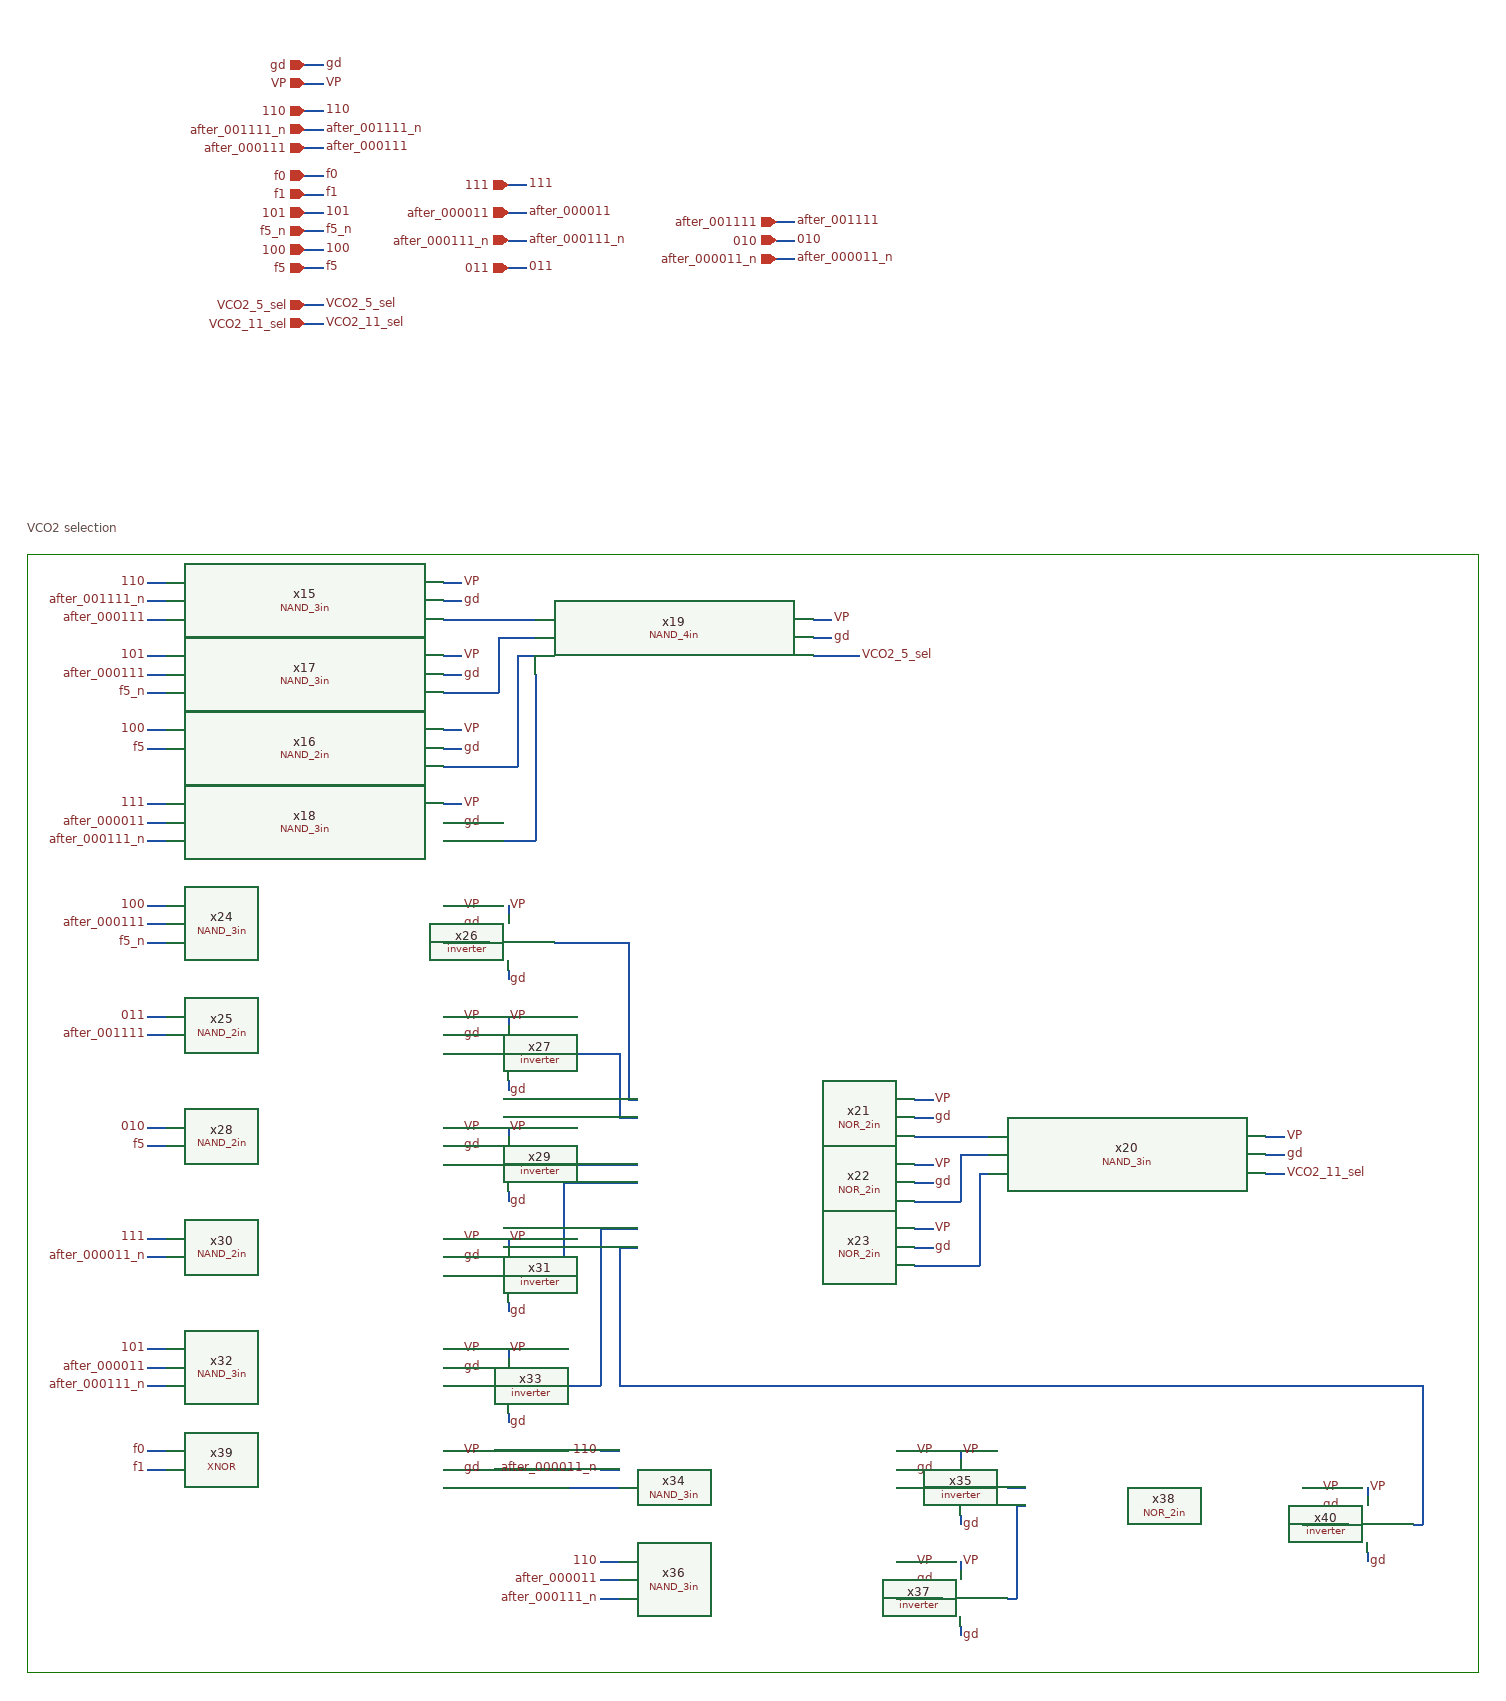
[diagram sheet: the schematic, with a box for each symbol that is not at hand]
v {xschem version=3.4.8RC file_version=1.3}
G {}
K {}
V {}
S {}
F {}
E {}
L 4 1700 -2770 1700 -2430 {}
L 4 1700 -2770 2040 -2770 {}
L 4 2040 -2770 2380 -2770 {}
L 4 2380 -2770 2720 -2770 {}
L 4 1700 -2440 1700 -2100 {}
L 4 1700 -2280 1700 -1940 {}
L 4 1700 -1950 1700 -1610 {}
L 4 1700 -1560 2040 -1560 {}
L 4 2040 -1560 2380 -1560 {}
L 4 2380 -1560 2720 -1560 {}
L 4 1700 -1900 1700 -1560 {}
L 4 2710 -2770 3050 -2770 {}
L 4 3270 -1900 3270 -1560 {}
L 4 2700 -1560 3040 -1560 {}
L 4 2930 -1560 3270 -1560 {}
L 4 3270 -2230 3270 -1890 {}
L 4 3270 -2570 3270 -2230 {}
L 4 3270 -2770 3270 -2430 {}
L 4 2930 -2770 3270 -2770 {}
T {VCO2 selection} 1700 -2810 0 0 0.4 0.4 {}
N 2150 -2720 2170 -2720 {lab=gd}
N 2150 -2740 2170 -2740 {lab=VP}
N 2150 -2560 2170 -2560 {lab=gd}
N 2150 -2580 2170 -2580 {lab=VP}
N 2150 -2640 2170 -2640 {lab=gd}
N 2150 -2660 2170 -2660 {lab=VP}
N 2150 -2480 2170 -2480 {lab=gd}
N 2150 -2500 2170 -2500 {lab=VP}
N 1830 -2740 1850 -2740 {lab=110}
N 1830 -2720 1850 -2720 {lab=after_001111_n}
N 1830 -2700 1850 -2700 {lab=after_000111}
N 1830 -2660 1850 -2660 {lab=101}
N 1830 -2640 1850 -2640 {lab=after_000111}
N 1830 -2620 1850 -2620 {lab=f5_n}
N 1830 -2500 1850 -2500 {lab=111}
N 1830 -2460 1850 -2460 {lab=after_000111_n}
N 1830 -2580 1850 -2580 {lab=100}
N 1830 -2560 1850 -2560 {lab=f5}
N 2150 -2700 2250 -2700 {lab=#net1}
N 2150 -2620 2210 -2620 {lab=#net2}
N 2210 -2680 2210 -2620 {lab=#net2}
N 2210 -2680 2250 -2680 {lab=#net2}
N 2230 -2660 2250 -2660 {lab=#net3}
N 2230 -2660 2230 -2540 {lab=#net3}
N 2150 -2540 2230 -2540 {lab=#net3}
N 2150 -2460 2250 -2460 {lab=#net4}
N 2250 -2640 2250 -2460 {lab=#net4}
N 2550 -2680 2570 -2680 {lab=gd}
N 2550 -2700 2570 -2700 {lab=VP}
N 2550 -2660 2600 -2660 {lab=VCO2_5_sel}
N 2660 -2160 2680 -2160 {lab=gd}
N 2660 -2180 2680 -2180 {lab=VP}
N 2660 -2090 2680 -2090 {lab=gd}
N 2660 -2110 2680 -2110 {lab=VP}
N 2660 -2020 2680 -2020 {lab=gd}
N 2660 -2040 2680 -2040 {lab=VP}
N 3040 -2120 3060 -2120 {lab=gd}
N 3040 -2140 3060 -2140 {lab=VP}
N 2660 -2140 2740 -2140 {lab=#net5}
N 2660 -2070 2710 -2070 {lab=#net6}
N 2710 -2120 2710 -2070 {lab=#net6}
N 2710 -2120 2740 -2120 {lab=#net6}
N 2730 -2100 2740 -2100 {lab=#net7}
N 2730 -2100 2730 -2000 {lab=#net7}
N 2660 -2000 2730 -2000 {lab=#net7}
N 2150 -2370 2170 -2370 {lab=gd}
N 2150 -2390 2170 -2390 {lab=VP}
N 2150 -2250 2170 -2250 {lab=gd}
N 2150 -2270 2170 -2270 {lab=VP}
N 2220 -2320 2220 -2310 {lab=gd}
N 2220 -2390 2220 -2380 {lab=VP}
N 2150 -2350 2200 -2350 {lab=#net8}
N 2270 -2350 2350 -2350 {lab=#net9}
N 2220 -2200 2220 -2190 {lab=gd}
N 2220 -2270 2220 -2260 {lab=VP}
N 2150 -2230 2200 -2230 {lab=#net10}
N 2270 -2230 2340 -2230 {lab=#net11}
N 2150 -2130 2170 -2130 {lab=gd}
N 2150 -2150 2170 -2150 {lab=VP}
N 2220 -2080 2220 -2070 {lab=gd}
N 2220 -2150 2220 -2140 {lab=VP}
N 2150 -2110 2200 -2110 {lab=#net12}
N 2270 -2110 2360 -2110 {lab=#net13}
N 2150 -2010 2170 -2010 {lab=gd}
N 2150 -2030 2170 -2030 {lab=VP}
N 2220 -1960 2220 -1950 {lab=gd}
N 2220 -2030 2220 -2020 {lab=VP}
N 2150 -1990 2200 -1990 {lab=#net14}
N 2270 -1990 2280 -1990 {lab=#net15}
N 2150 -1890 2170 -1890 {lab=gd}
N 2150 -1910 2170 -1910 {lab=VP}
N 2220 -1840 2220 -1830 {lab=gd}
N 2220 -1910 2220 -1900 {lab=VP}
N 2150 -1870 2200 -1870 {lab=#net16}
N 2270 -1870 2320 -1870 {lab=#net17}
N 2640 -1780 2660 -1780 {lab=gd}
N 2640 -1800 2660 -1800 {lab=VP}
N 2710 -1730 2710 -1720 {lab=gd}
N 2710 -1800 2710 -1790 {lab=VP}
N 2640 -1760 2690 -1760 {lab=#net18}
N 2760 -1760 2780 -1760 {lab=#net19}
N 2640 -1660 2660 -1660 {lab=gd}
N 2640 -1680 2660 -1680 {lab=VP}
N 2710 -1610 2710 -1600 {lab=gd}
N 2710 -1680 2710 -1670 {lab=VP}
N 2640 -1640 2690 -1640 {lab=#net20}
N 2760 -1640 2770 -1640 {lab=#net21}
N 2350 -2180 2360 -2180 {lab=#net9}
N 2350 -2350 2350 -2180 {lab=#net9}
N 2340 -2230 2340 -2160 {lab=#net11}
N 2340 -2160 2360 -2160 {lab=#net11}
N 2280 -2090 2280 -1990 {lab=#net15}
N 2280 -2090 2360 -2090 {lab=#net15}
N 2320 -2040 2320 -1870 {lab=#net17}
N 2320 -2040 2360 -2040 {lab=#net17}
N 3080 -1740 3100 -1740 {lab=gd}
N 3080 -1760 3100 -1760 {lab=VP}
N 3150 -1690 3150 -1680 {lab=gd}
N 3150 -1760 3150 -1750 {lab=VP}
N 3080 -1720 3130 -1720 {lab=#net22}
N 3200 -1720 3210 -1720 {lab=#net23}
N 2770 -1740 2780 -1740 {lab=#net21}
N 2770 -1740 2770 -1640 {lab=#net21}
N 2340 -2020 2340 -1870 {lab=#net23}
N 2340 -2020 2360 -2020 {lab=#net23}
N 2150 -1780 2170 -1780 {lab=gd}
N 2150 -1800 2170 -1800 {lab=VP}
N 3210 -1870 3210 -1720 {lab=#net23}
N 2340 -1870 3210 -1870 {lab=#net23}
N 1830 -2480 1850 -2480 {lab=after_000011}
N 1830 -2390 1850 -2390 {lab=100}
N 1830 -2350 1850 -2350 {lab=f5_n}
N 1830 -2370 1850 -2370 {lab=after_000111}
N 1830 -1910 1850 -1910 {lab=101}
N 1830 -1870 1850 -1870 {lab=after_000111_n}
N 1830 -1890 1850 -1890 {lab=after_000011}
N 2320 -1680 2340 -1680 {lab=110}
N 2320 -1640 2340 -1640 {lab=after_000111_n}
N 2320 -1660 2340 -1660 {lab=after_000011}
N 1830 -1800 1850 -1800 {lab=f0}
N 1830 -1780 1850 -1780 {lab=f1}
N 2320 -1800 2340 -1800 {lab=110}
N 2320 -1780 2340 -1780 {lab=after_000011_n}
N 1830 -2150 1850 -2150 {lab=010}
N 1830 -2130 1850 -2130 {lab=f5}
N 1830 -2270 1850 -2270 {lab=011}
N 1830 -2250 1850 -2250 {lab=after_001111}
N 1830 -2030 1850 -2030 {lab=111}
N 1830 -2010 1850 -2010 {lab=after_000011_n}
N 2150 -1760 2340 -1760 {lab=#net24}
N 3040 -2100 3060 -2100 {lab=VCO2_11_sel}
N 2000 -3300 2020 -3300 {lab=gd}
N 2000 -3280 2020 -3280 {lab=VP}
N 2000 -3230 2020 -3230 {lab=after_001111_n}
N 2000 -3210 2020 -3210 {lab=after_000111}
N 2000 -3180 2020 -3180 {lab=f0}
N 2000 -3160 2020 -3160 {lab=f1}
N 2000 -3250 2020 -3250 {lab=110}
N 2000 -3020 2020 -3020 {lab=VCO2_11_sel}
N 2000 -3040 2020 -3040 {lab=VCO2_5_sel}
N 2000 -3140 2020 -3140 {lab=101}
N 2000 -3120 2020 -3120 {lab=f5_n}
N 2000 -3100 2020 -3100 {lab=100}
N 2000 -3080 2020 -3080 {lab=f5}
N 2220 -3080 2240 -3080 {lab=011}
N 2220 -3110 2240 -3110 {lab=after_000111_n}
N 2220 -3140 2240 -3140 {lab=after_000011}
N 2220 -3170 2240 -3170 {lab=111}
N 2510 -3090 2530 -3090 {lab=after_000011_n}
N 2510 -3110 2530 -3110 {lab=010}
N 2510 -3130 2530 -3130 {lab=after_001111}
C {lab_wire.sym} 1830 -2660 0 0 {name=p124 sig_type=std_logic lab=101}
C {lab_wire.sym} 1830 -2740 0 0 {name=p125 sig_type=std_logic lab=110}
C {NAND_3in.sym} 2000 -2720 0 0 {name=x15}
C {NAND_2in.sym} 2000 -2560 0 0 {name=x16}
C {lab_wire.sym} 2170 -2740 2 0 {name=p130 sig_type=std_logic lab=VP}
C {lab_wire.sym} 2170 -2720 2 0 {name=p131 sig_type=std_logic lab=gd}
C {lab_wire.sym} 2170 -2580 2 0 {name=p132 sig_type=std_logic lab=VP}
C {lab_wire.sym} 2170 -2560 2 0 {name=p133 sig_type=std_logic lab=gd}
C {NAND_3in.sym} 2000 -2640 0 0 {name=x17}
C {lab_wire.sym} 2170 -2660 2 0 {name=p134 sig_type=std_logic lab=VP}
C {lab_wire.sym} 2170 -2640 2 0 {name=p135 sig_type=std_logic lab=gd}
C {NAND_3in.sym} 2000 -2480 0 0 {name=x18}
C {lab_wire.sym} 2170 -2500 2 0 {name=p136 sig_type=std_logic lab=VP}
C {lab_wire.sym} 2170 -2480 2 0 {name=p137 sig_type=std_logic lab=gd}
C {lab_wire.sym} 1830 -2580 0 0 {name=p140 sig_type=std_logic lab=100}
C {lab_wire.sym} 1830 -2500 0 0 {name=p141 sig_type=std_logic lab=111}
C {lab_wire.sym} 1830 -2720 0 0 {name=p142 sig_type=std_logic lab=after_001111_n}
C {lab_wire.sym} 1830 -2700 0 0 {name=p145 sig_type=std_logic lab=after_000111}
C {lab_wire.sym} 1830 -2640 0 0 {name=p146 sig_type=std_logic lab=after_000111}
C {lab_wire.sym} 1830 -2620 0 0 {name=p147 sig_type=std_logic lab=f5_n}
C {lab_wire.sym} 1830 -2560 0 0 {name=p90 sig_type=std_logic lab=f5}
C {lab_wire.sym} 1830 -2480 0 0 {name=p91 sig_type=std_logic lab=after_000011}
C {lab_wire.sym} 1830 -2460 0 0 {name=p94 sig_type=std_logic lab=after_000111_n}
C {NAND_4in.sym} 2400 -2670 0 0 {name=x19}
C {lab_wire.sym} 2570 -2700 2 0 {name=p148 sig_type=std_logic lab=VP}
C {lab_wire.sym} 2570 -2680 2 0 {name=p149 sig_type=std_logic lab=gd}
C {lab_wire.sym} 2600 -2660 2 0 {name=p150 sig_type=std_logic lab=VCO2_5_sel}
C {NAND_3in.sym} 2890 -2120 0 0 {name=x20}
C {NOR_2in.sym} 2510 -2160 0 0 {name=x21}
C {lab_wire.sym} 2680 -2180 2 0 {name=p151 sig_type=std_logic lab=VP}
C {lab_wire.sym} 2680 -2160 2 0 {name=p152 sig_type=std_logic lab=gd}
C {NOR_2in.sym} 2510 -2090 0 0 {name=x22}
C {lab_wire.sym} 2680 -2110 2 0 {name=p153 sig_type=std_logic lab=VP}
C {lab_wire.sym} 2680 -2090 2 0 {name=p154 sig_type=std_logic lab=gd}
C {NOR_2in.sym} 2510 -2020 0 0 {name=x23}
C {lab_wire.sym} 2680 -2040 2 0 {name=p155 sig_type=std_logic lab=VP}
C {lab_wire.sym} 2680 -2020 2 0 {name=p156 sig_type=std_logic lab=gd}
C {lab_wire.sym} 3060 -2140 2 0 {name=p157 sig_type=std_logic lab=VP}
C {lab_wire.sym} 3060 -2120 2 0 {name=p158 sig_type=std_logic lab=gd}
C {NAND_3in.sym} 2000 -2370 0 0 {name=x24}
C {lab_wire.sym} 2170 -2390 2 0 {name=p159 sig_type=std_logic lab=VP}
C {lab_wire.sym} 2170 -2370 2 0 {name=p160 sig_type=std_logic lab=gd}
C {NAND_2in.sym} 2000 -2250 0 0 {name=x25}
C {lab_wire.sym} 2170 -2270 2 0 {name=p161 sig_type=std_logic lab=VP}
C {lab_wire.sym} 2170 -2250 2 0 {name=p162 sig_type=std_logic lab=gd}
C {inverter.sym} 2220 -2350 0 0 {name=x26}
C {lab_wire.sym} 2220 -2390 0 1 {name=p163 sig_type=std_logic lab=VP}
C {lab_wire.sym} 2220 -2310 2 0 {name=p164 sig_type=std_logic lab=gd}
C {inverter.sym} 2220 -2230 0 0 {name=x27}
C {lab_wire.sym} 2220 -2270 0 1 {name=p165 sig_type=std_logic lab=VP}
C {lab_wire.sym} 2220 -2190 2 0 {name=p166 sig_type=std_logic lab=gd}
C {NAND_2in.sym} 2000 -2130 0 0 {name=x28}
C {lab_wire.sym} 2170 -2150 2 0 {name=p167 sig_type=std_logic lab=VP}
C {lab_wire.sym} 2170 -2130 2 0 {name=p168 sig_type=std_logic lab=gd}
C {inverter.sym} 2220 -2110 0 0 {name=x29}
C {lab_wire.sym} 2220 -2150 0 1 {name=p169 sig_type=std_logic lab=VP}
C {lab_wire.sym} 2220 -2070 2 0 {name=p170 sig_type=std_logic lab=gd}
C {NAND_2in.sym} 2000 -2010 0 0 {name=x30}
C {lab_wire.sym} 2170 -2030 2 0 {name=p171 sig_type=std_logic lab=VP}
C {lab_wire.sym} 2170 -2010 2 0 {name=p172 sig_type=std_logic lab=gd}
C {inverter.sym} 2220 -1990 0 0 {name=x31}
C {lab_wire.sym} 2220 -2030 0 1 {name=p173 sig_type=std_logic lab=VP}
C {lab_wire.sym} 2220 -1950 2 0 {name=p174 sig_type=std_logic lab=gd}
C {NAND_3in.sym} 2000 -1890 0 0 {name=x32}
C {lab_wire.sym} 2170 -1910 2 0 {name=p175 sig_type=std_logic lab=VP}
C {lab_wire.sym} 2170 -1890 2 0 {name=p176 sig_type=std_logic lab=gd}
C {inverter.sym} 2220 -1870 0 0 {name=x33}
C {lab_wire.sym} 2220 -1910 0 1 {name=p177 sig_type=std_logic lab=VP}
C {lab_wire.sym} 2220 -1830 2 0 {name=p178 sig_type=std_logic lab=gd}
C {NAND_3in.sym} 2490 -1780 0 0 {name=x34}
C {lab_wire.sym} 2660 -1800 2 0 {name=p179 sig_type=std_logic lab=VP}
C {lab_wire.sym} 2660 -1780 2 0 {name=p180 sig_type=std_logic lab=gd}
C {inverter.sym} 2710 -1760 0 0 {name=x35}
C {lab_wire.sym} 2710 -1800 0 1 {name=p181 sig_type=std_logic lab=VP}
C {lab_wire.sym} 2710 -1720 2 0 {name=p182 sig_type=std_logic lab=gd}
C {NAND_3in.sym} 2490 -1660 0 0 {name=x36}
C {lab_wire.sym} 2660 -1680 2 0 {name=p183 sig_type=std_logic lab=VP}
C {lab_wire.sym} 2660 -1660 2 0 {name=p184 sig_type=std_logic lab=gd}
C {inverter.sym} 2710 -1640 0 0 {name=x37}
C {lab_wire.sym} 2710 -1680 0 1 {name=p185 sig_type=std_logic lab=VP}
C {lab_wire.sym} 2710 -1600 2 0 {name=p186 sig_type=std_logic lab=gd}
C {NOR_2in.sym} 2930 -1740 0 0 {name=x38}
C {lab_wire.sym} 3100 -1760 2 0 {name=p189 sig_type=std_logic lab=VP}
C {lab_wire.sym} 3100 -1740 2 0 {name=p190 sig_type=std_logic lab=gd}
C {inverter.sym} 3150 -1720 0 0 {name=x40}
C {lab_wire.sym} 3150 -1760 0 1 {name=p191 sig_type=std_logic lab=VP}
C {lab_wire.sym} 3150 -1680 2 0 {name=p192 sig_type=std_logic lab=gd}
C {XNOR.sym} 2000 -1780 0 0 {name=x39}
C {lab_wire.sym} 2170 -1800 2 0 {name=p187 sig_type=std_logic lab=VP}
C {lab_wire.sym} 2170 -1780 2 0 {name=p188 sig_type=std_logic lab=gd}
C {lab_wire.sym} 1830 -2390 0 0 {name=p193 sig_type=std_logic lab=100}
C {lab_wire.sym} 1830 -2270 0 0 {name=p194 sig_type=std_logic lab=011}
C {lab_wire.sym} 1830 -2150 0 0 {name=p195 sig_type=std_logic lab=010}
C {lab_wire.sym} 1830 -2030 0 0 {name=p196 sig_type=std_logic lab=111}
C {lab_wire.sym} 1830 -1910 0 0 {name=p197 sig_type=std_logic lab=101}
C {lab_wire.sym} 2320 -1800 0 0 {name=p199 sig_type=std_logic lab=110}
C {lab_wire.sym} 2320 -1680 0 0 {name=p200 sig_type=std_logic lab=110}
C {lab_wire.sym} 1830 -2370 0 0 {name=p198 sig_type=std_logic lab=after_000111}
C {lab_wire.sym} 1830 -2350 0 0 {name=p201 sig_type=std_logic lab=f5_n}
C {lab_wire.sym} 1830 -2250 0 0 {name=p202 sig_type=std_logic lab=after_001111}
C {lab_wire.sym} 1830 -2130 0 0 {name=p203 sig_type=std_logic lab=f5}
C {lab_wire.sym} 1830 -2010 0 0 {name=p204 sig_type=std_logic lab=after_000011_n}
C {lab_wire.sym} 1830 -1890 0 0 {name=p205 sig_type=std_logic lab=after_000011}
C {lab_wire.sym} 1830 -1870 0 0 {name=p206 sig_type=std_logic lab=after_000111_n}
C {lab_wire.sym} 2320 -1780 0 0 {name=p207 sig_type=std_logic lab=after_000011_n}
C {lab_wire.sym} 2320 -1660 0 0 {name=p208 sig_type=std_logic lab=after_000011}
C {lab_wire.sym} 2320 -1640 0 0 {name=p209 sig_type=std_logic lab=after_000111_n}
C {lab_wire.sym} 1830 -1800 0 0 {name=p210 sig_type=std_logic lab=f0}
C {lab_wire.sym} 1830 -1780 0 0 {name=p211 sig_type=std_logic lab=f1}
C {lab_wire.sym} 3060 -2100 2 0 {name=p212 sig_type=std_logic lab=VCO2_11_sel}
C {iopin.sym} 2000 -3300 2 0 {name=p46 lab=gd}
C {lab_wire.sym} 2020 -3300 2 0 {name=p53 sig_type=std_logic lab=gd}
C {iopin.sym} 2000 -3280 2 0 {name=p54 lab=VP}
C {ipin.sym} 2000 -3230 0 0 {name=p2 lab=after_001111_n}
C {lab_wire.sym} 2020 -3230 2 0 {name=p56 sig_type=std_logic lab=after_001111_n}
C {ipin.sym} 2000 -3210 0 0 {name=p57 lab=after_000111}
C {lab_wire.sym} 2020 -3210 2 0 {name=p58 sig_type=std_logic lab=after_000111}
C {ipin.sym} 2000 -3180 0 0 {name=p59 lab=f0}
C {lab_wire.sym} 2020 -3180 2 0 {name=p60 sig_type=std_logic lab=f0}
C {ipin.sym} 2000 -3160 0 0 {name=p61 lab=f1}
C {lab_wire.sym} 2020 -3160 2 0 {name=p63 sig_type=std_logic lab=f1}
C {ipin.sym} 2000 -3250 0 0 {name=p20 lab=110}
C {lab_wire.sym} 2020 -3250 2 0 {name=p21 sig_type=std_logic lab=110}
C {lab_wire.sym} 2020 -3280 2 0 {name=p1 sig_type=std_logic lab=VP}
C {opin.sym} 2000 -3020 0 1 {name=p6 lab=VCO2_11_sel}
C {lab_wire.sym} 2020 -3020 2 0 {name=p7 sig_type=std_logic lab=VCO2_11_sel}
C {opin.sym} 2000 -3040 0 1 {name=p14 lab=VCO2_5_sel}
C {lab_wire.sym} 2020 -3040 2 0 {name=p15 sig_type=std_logic lab=VCO2_5_sel}
C {ipin.sym} 2000 -3140 0 0 {name=p19 lab=101}
C {lab_wire.sym} 2020 -3140 2 0 {name=p22 sig_type=std_logic lab=101}
C {ipin.sym} 2000 -3120 0 0 {name=p23 lab=f5_n}
C {lab_wire.sym} 2020 -3120 2 0 {name=p24 sig_type=std_logic lab=f5_n}
C {ipin.sym} 2000 -3100 0 0 {name=p25 lab=100}
C {lab_wire.sym} 2020 -3100 2 0 {name=p26 sig_type=std_logic lab=100}
C {ipin.sym} 2000 -3080 0 0 {name=p27 lab=f5}
C {lab_wire.sym} 2020 -3080 2 0 {name=p28 sig_type=std_logic lab=f5}
C {ipin.sym} 2220 -3080 0 0 {name=p3 lab=011}
C {lab_wire.sym} 2240 -3080 2 0 {name=p4 sig_type=std_logic lab=011}
C {ipin.sym} 2220 -3110 0 0 {name=p5 lab=after_000111_n}
C {lab_wire.sym} 2240 -3110 2 0 {name=p8 sig_type=std_logic lab=after_000111_n}
C {ipin.sym} 2220 -3140 0 0 {name=p9 lab=after_000011}
C {lab_wire.sym} 2240 -3140 2 0 {name=p10 sig_type=std_logic lab=after_000011}
C {ipin.sym} 2220 -3170 0 0 {name=p11 lab=111}
C {lab_wire.sym} 2240 -3170 2 0 {name=p12 sig_type=std_logic lab=111}
C {ipin.sym} 2510 -3090 0 0 {name=p17 lab=after_000011_n}
C {lab_wire.sym} 2530 -3090 2 0 {name=p18 sig_type=std_logic lab=after_000011_n}
C {ipin.sym} 2510 -3110 0 0 {name=p29 lab=010}
C {lab_wire.sym} 2530 -3110 2 0 {name=p30 sig_type=std_logic lab=010}
C {ipin.sym} 2510 -3130 0 0 {name=p31 lab=after_001111}
C {lab_wire.sym} 2530 -3130 2 0 {name=p32 sig_type=std_logic lab=after_001111}
